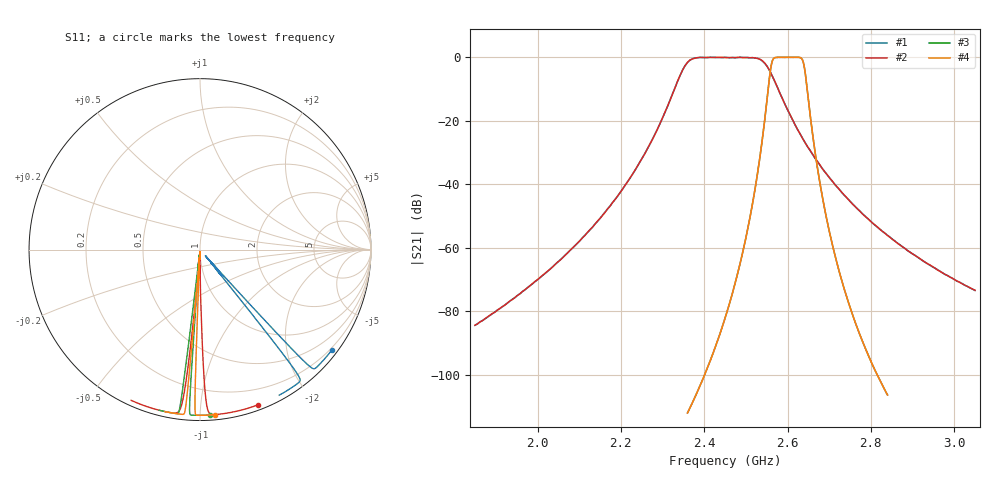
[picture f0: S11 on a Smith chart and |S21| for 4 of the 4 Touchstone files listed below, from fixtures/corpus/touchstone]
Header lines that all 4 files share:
! written by passband
# GHZ S DB R 50
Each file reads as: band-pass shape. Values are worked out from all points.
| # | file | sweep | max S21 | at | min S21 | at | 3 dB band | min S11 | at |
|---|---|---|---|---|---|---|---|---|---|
| 1 | QPF4216_revA.s2p | 1.85 GHz to 3.05 GHz | -0.01 dB | 2.414 GHz | -84.4 dB | 1.85 GHz | 2.354 GHz-2.546 GHz | -26.4 dB | 2.414 GHz |
| 2 | QPF4216_revB.s2p | 1.85 GHz to 3.05 GHz | 0.00 dB | 2.438 GHz | -84.3 dB | 1.85 GHz | 2.354 GHz-2.546 GHz | -39.7 dB | 2.438 GHz |
| 3 | QPQ1904_revA.s2p | 2.36 GHz to 2.84 GHz | 0.00 dB | 2.578 GHz | -112.0 dB | 2.36 GHz | 2.562 GHz-2.638 GHz | -31.6 dB | 2.578 GHz |
| 4 | QPQ1904_revB.s2p | 2.36 GHz to 2.84 GHz | 0.00 dB | 2.605 GHz | -112.0 dB | 2.36 GHz | 2.562 GHz-2.638 GHz | -38.1 dB | 2.605 GHz |
